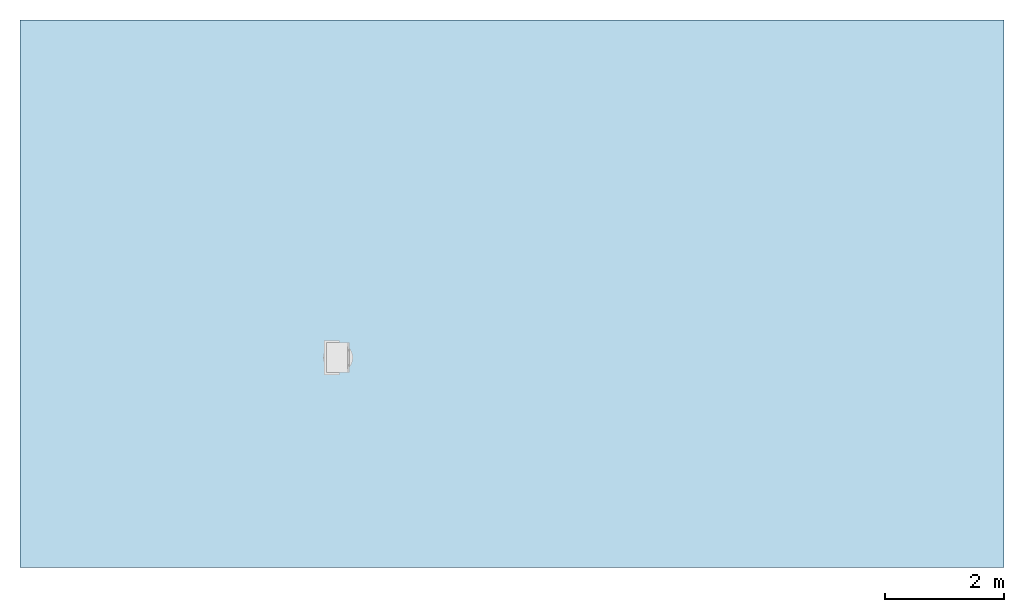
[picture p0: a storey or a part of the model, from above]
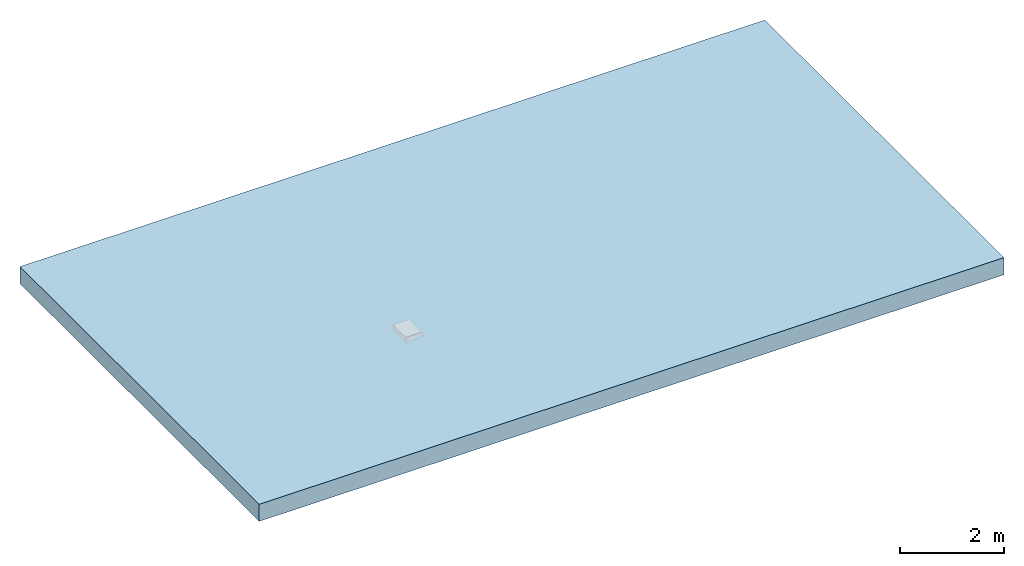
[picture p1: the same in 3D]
Properties of the parts of a building model (IFC2X3)

# File
Description: ViewDefinition [CoordinationView]
Time: 2013-09-04T09:40:21
Written by: Autodesk Revit 2013
Made in: 20120221_2030(x64)

# IfcProject, Project Number
LongName: Project Name; Phase: Project Status

# IfcSite, Default
RefLatitude: 42, 21, 30, 344238; RefLongitude: -71, -3, -35, -194702; RefElevation: 0 mm

# IfcBuilding
Pset_BuildingCommon - NumberOfStoreys: 1
Other - Project Address: ## Street City, State Zip; Project Status: Project Status; Project Issue Date: Issue Date; Project Name: Project Name; Client Name: Owner; Project Number: Project Number

# IfcBuildingStorey, Level 1
LongName: Level 1; Elevation: 0 mm
Constraints - Elevation Base: 0; Elevation: 0 mm
Graphics - Symbol at End 1 Default: no; Symbol at End 2 Default: yes; Line Weight: 1; Symbol: M_Level Head - Circle: M_Level Head - Circle; Color: 0; Line Pattern: Center
Identity Data - Name: Level 1; Building Story: yes; Structural: no
Dimensions - Computation Height: 0 mm

# IfcBuildingElementProxy: 4185 - Top and road gully connector Ø450mm - KD615, Civil-Drainage-Channel-ACO-KerbDrain-HB Gully units:4185 - Top and road gully connector Ø450mm - KD615:4185 - Top and road gully connector Ø450mm - KD615:309626
In: Level 1
Material: Cast Iron, ACO Polmer Concrete., Gully Colour
Constraints - Moves With Nearby Elements: no; Level: Level: Level 1
Dimensions - Volume: 24335846 mm3; Shallow Base Depth: 6000 mm; Top and bottom 4979 void depth: 6000 mm; Gully Connector Void Start: 0 mm; Deep Base Void Depth: 6000 mm; Gully Connector Void End: 40 mm
Phasing - Phase Created: New Construction
Pset_BuildingElementProxyCommon - Reference: 4185 - Top and road gully connector Ø450mm - KD615
Green Building Properties - Gully Cover/Frame Recyclable: Fully recyclable; Gully Base Recycled Material Content: 20% minimum; Gully Base Recyclable: Fully recyclable; Gully Cover/Frame Recycled Material Content: Between 40% - 90%
Data - Hydraulic Performance: http://www.aco.co.uk/download.php?id=120; Invert Depth: N/A; ACO Hydraulic Design Software: http://www.acodesign.co.uk; Installation - Concrete Grade: Refer to brochure; Drainage Slot Intake area: 14592mm²/m; Drainage Slot Width: 50mm; Product Standard: BS EN 1433:2002, CE marked, Kitemarked; Product Dimensions: 500mm x 390mm x 545mm (LxWxH); Load Class: A 15 - D 400; Product Weight: 88.1 Kg
Identity Data - Telephone: +44 (0)1462 816666; Product brochure: http://www.aco.co.uk/download.php?id=120; Maintenance guidelines: http://www.aco.co.uk/download.php?id=120; URL: www.aco.co.uk; Model: ACO KerbDrain Half Battered Gully Units; Assembly Code: D2040; e-mail Technical: technical@aco.co.uk; Fax: +44 (0)1462 815895; Installation guidelines: http://www.aco.co.uk/download.php?id=120; OmniClass Title: Rainwater Removal; Address: ACO Business Park, Hitchin Road, Shefford, Bedfordshire, United Kingdom SG17 5TE; Price: POA - contact ACO; Product Page URL: http://www.aco.co.uk/product_detail.php?id=3; Type Comments: ACO KerbDrain Half Battered Gully Units - Top & Road Gully Connector Ø450mm KD615; Assembly Description: Rain Water Drainage; Product Code: 4185; Cost: 0; e-mail Sales: customersupport@aco.co.uk; OmniClass Number: 23.70.50.24; Model Description: Combined kerb and drainage system; Manufacturer: ACO Technologies plc - ACO Water Management Division
General - SerialNumber: 0.000000; TagNumber: 0.000000
Construction - Shallow base: no; Top and road gully connector: yes; Deep Base: no; Top assembly: yes; Top and roddable deep base assembly KD612RE: no
Materials and Finishes - Gully Base Colour: Brown; Gully Cover/Frame Finish: Water Based Paint Coating; Gully Base Material: Vienite® Synthetic Resin Concrete; Gully Cover/Frame Colour: Black; Gully Cover/Frame Material: Ductile Iron
Other - Revision: 1; CreatedBy: www.aco.co.uk

# IfcOpeningElement: Opening (2)
In: Level 1
Phasing - Phase Created: New Construction
Dimensions - Volume: 60509169587 mm3; Thickness: 400 mm; Area: 151275000 mm2; Perimeter: 51360 mm
Structural - Structural: no; Enable Analytical Model: no
Constraints - Room Bounding: yes; Height Offset From Level: 0 mm; Related to Mass: no; Level: Level: Level 1
Analytical Properties - Roughness: 1; Absorptance: 0.1
Graphics - Coarse Scale Fill Color: 0
Construction - Default Thickness: 400 mm; Function: 0
Materials and Finishes - Structural Material: Plant

# IfcSlab: Floor:Generic Floor - 400mm, Floor:Generic Floor - 400mm:193825
In: Level 1
PredefinedType: FLOOR; Material: Plant 400 mm
Phasing - Phase Created: New Construction
Dimensions - Volume: 60509169587 mm3; Thickness: 400 mm; Area: 151275000 mm2; Perimeter: 51360 mm
Structural - Structural: no; Enable Analytical Model: no
Constraints - Room Bounding: yes; Height Offset From Level: 0 mm; Related to Mass: no; Level: Level: Level 1
Pset_SlabCommon - Reference: Generic Floor - 400mm; IsExternal: no; LoadBearing: yes
Analytical Properties - Roughness: 1; Absorptance: 0.1
Graphics - Coarse Scale Fill Color: 0
Construction - Default Thickness: 400 mm; Function: 0
Materials and Finishes - Structural Material: Plant
